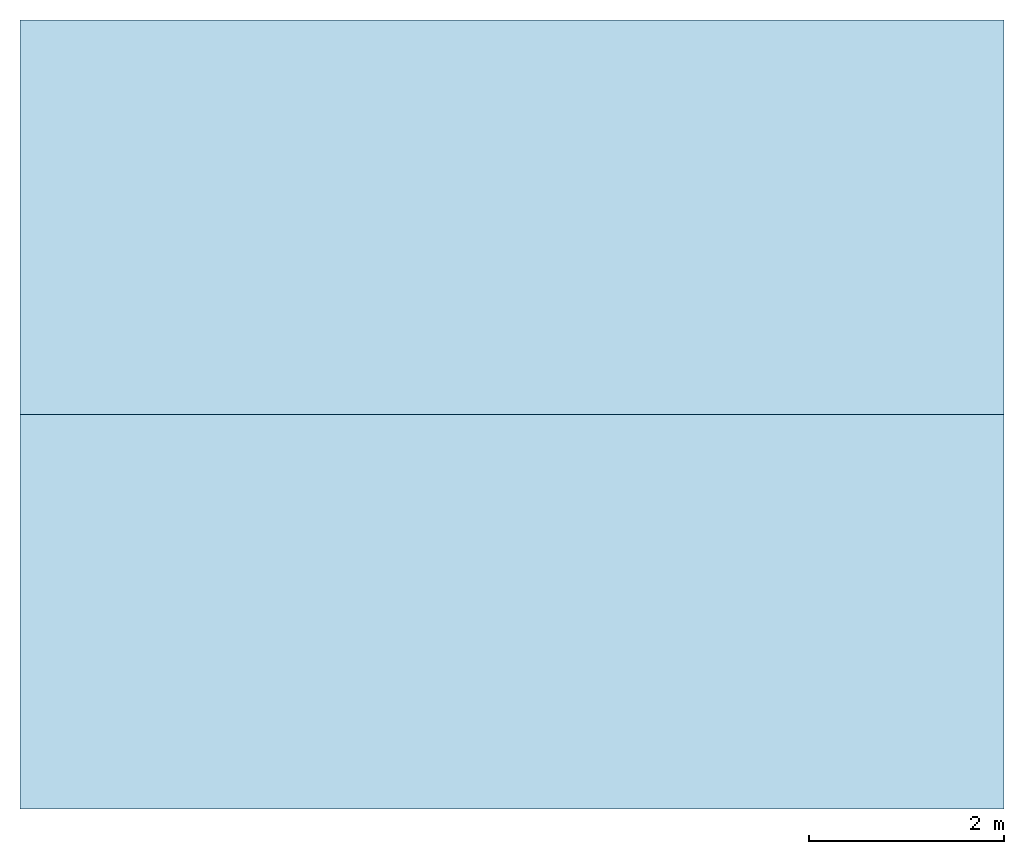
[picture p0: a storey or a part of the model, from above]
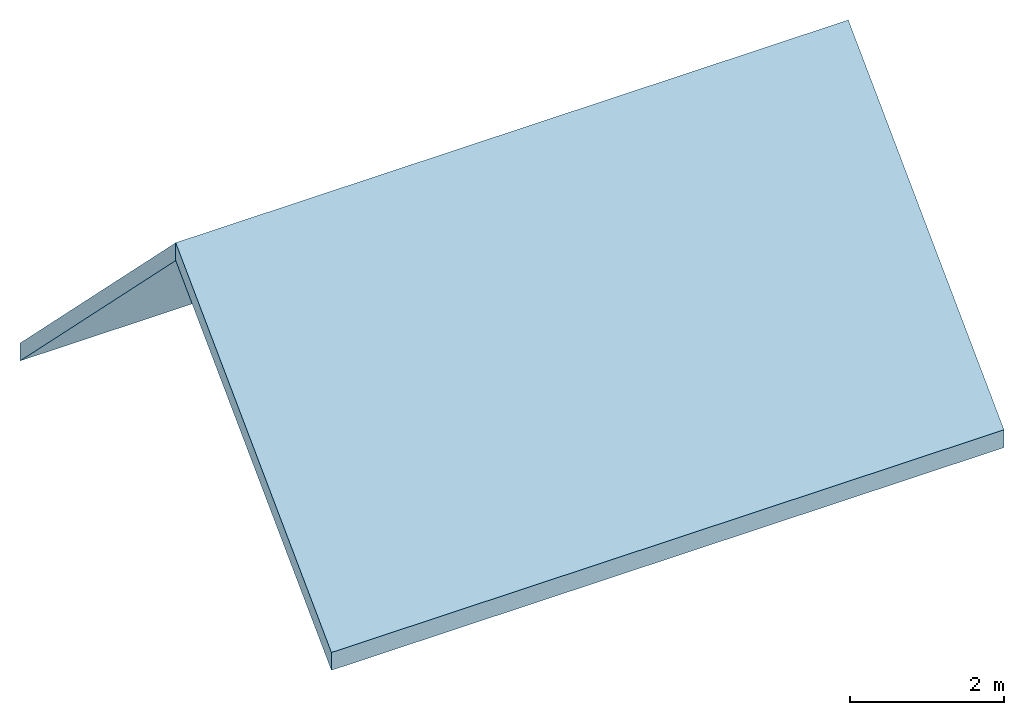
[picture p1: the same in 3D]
Properties of the parts of a building model (IFC2X3)

# File
Description: ViewDefinition [CoordinationView]
Time: 2014-10-18T11:21:26
Written by: The EXPRESS Data Manager Version 5.01.0100.02.64mod : 6 Jun 2012
Made in: 20130308_1515(x64) - Exporter 2014.0.2013.0308 - Default UI
Comment: STEP Physical File produced by: The EXPRESS Data Manager Version 5.01.0100.02.64mod : 6 Jun 2012 * Module: EDMstepFileFactory/EDMstandAlone * Creation date: Sat Oct 18 11:21:26 2014 * Host: PC-david * Database: C:\Users\DEVEAUX\AppData\Local\Temp\{E35612F2-2FBD-463F-806F-01D8CE0484EC}\ifc * Database version: 5507 * Database creation date: Sat Oct 18 11:21:22 2014 * Schema: IFC2X3 * Model: DataRepository.ifc * Model creation date: Sat Oct 18 11:21:22 2014 * Header model: DataRepository.ifc_HeaderModel * Header model creation date: Sat Oct 18 11:21:22 2014 * EDMuser: sdai-user * EDMgroup: sdai-group * License ID and type: 5605 : Permanent license. Expiry date: * EDMstepFileFactory options: 020000

# IfcProject
LongName: C:\Users\DEVEAUX\Documents\maison_01.ifc

# IfcSite, Default
RefLatitude: 48, 52, 53, 759999; RefLongitude: 2, 25, 58, 79999; RefElevation: 0 m

# IfcBuilding
Pset_BuildingCommon - NumberOfStoreys: 2

# IfcBuildingStorey (2)
Données d'identification - Structure: no; Etage de bâtiment: yes
Cotes - Hauteur de calcul: 0 m
Graphismes - Motif des lignes: Tiret point; Valeur par défaut du symbole à l'extrémité 2: yes; Epaisseur des lignes: 1; Valeur par défaut du symbole à l'extrémité 1: no; Couleur: 12632256; Symbole: FR_Marqueur de niveau - Point triangulaire: FR_Marqueur de niveau - Point triangulaire
Contraintes - Base de l'élévation: Point de base du projet
Name | LongName = Nom | Elevation (m) | Elévation (m)
Niveau 00 | Niveau 00 | 6.8783e-12 | 0
Niveau 01 | Niveau 01 | 3 | 3

# IfcSpace (9)
In: Niveau 00
InteriorOrExteriorSpace: INTERNAL
Contraintes - Limite supérieure: Niveau: Niveau 00; Niveau: Niveau: Niveau 00; Décalage limite: 2.4384 m; Décalage inférieur: 0 m
Phase de construction - Phase: Nouvelle construction
Cotes - Hauteur non liée: 2.4384 m; Hauteur de calcul: 0 m
Name | LongName = Nom | GSA BIM Area (m2) = Surface (m2) | Numéro | Périmètre (m) | Reference
10 | Séjour | 17.9204 | 10 | 17.15 | Séjour 10
11 | Cuisine | 7.00693 | 11 | 11.17 | Cuisine 11
12 | Entrée | 7.27615 | 12 | 14.07 | Entrée 12
13 | WC | 2.42 | 13 | 6.6 | WC 13
14 | S de B | 5.83 | 14 | 9.7 | S de B 14
15 | Rgt 1 | 0.945 | 15 | 4.35 | Rgt 1 15
16 | Rgt 2 | 0.945 | 16 | 4.35 | Rgt 2 16
17 | Chambre 1 | 8.3525 | 17 | 11.64 | Chambre 1 17
18 | Chambre 2 | 8.125 | 18 | 11.5 | Chambre 2 18

# IfcBuildingElementProxy: Texte 3D:Texte 3D 1
In: Niveau 00
Graphismes - Texte: Maison N°1; Alignement horizontal: Gauche
Phase de construction - Phase de création: Nouvelle construction
Cotes - Profondeur: 0.15 m
Données d'identification - Sous-catégorie: -2000151
Contraintes - Plan de construction: Niveau : Niveau 00
Pset_BuildingElementProxyCommon - Reference: Texte 3D 1
Texte - Italique: no; Taille du texte: 0.6 m; Police de texte: Arial; Gras: no

# IfcCovering: Plafond composé:Plafond avec isolation 2, Plafond composé:Plafond avec isolation 2:113292
In: Niveau 00
PredefinedType: CEILING; Material: Isolant 0.1 m, Faux-Plafond par Défaut 0.013 m
Cotes - Surface: 60.7796 m2; Volume: 6.86809 m3; Périmètre: 31.44 m
Contraintes - Limite de pièce: yes; Décalage par rapport au niveau: 2.6 m; Niveau: Niveau: Niveau 00
Phase de construction - Phase de création: Nouvelle construction
Pset_CoveringCommon - Reference: Plafond avec isolation 2; TotalThickness: 0.113 m
Propriétés analytiques - Coefficient d'absorbance: 0.1; Rugosité: 1
Construction - Epaisseur: 0.113 m
Graphismes - Couleur vue détail faible: 0

# IfcCovering: Plafond de base:Faux plafond 300 x 300 mm (2)
In: Niveau 00
PredefinedType: CEILING
Cotes - Périmètre: 31.44 m; Surface: 60.7796 m2
Phase de construction - Phase de création: Nouvelle construction
Contraintes - Limite de pièce: yes; Niveau: Niveau: Niveau 00; Décalage par rapport au niveau: 2.6 m
Pset_CoveringCommon - Reference: Faux plafond 300 x 300 mm
Propriétés analytiques - Rugosité: 1; Coefficient d'absorbance: 0.1
Matériaux et finitions - Matériau: Faux-Plafond par Défaut
Name (Plafond de base:Faux plafond 300 x 300 mm:...)
113275
113283

# IfcDoor: 143 x 204 - (140), FR_Double Vitrée Modèle 1:143 x 204 - (140):99876
In: Niveau 00
Type - OperationType: DOUBLE_DOOR_SINGLE_SWING; ParameterTakesPrecedence: no; Sizeable: no; Material: Poignée Porte, Dormants Portes, Verre, Panneaux Portes
OverallHeight: 2.075 m; OverallWidth: 1.5 m
Autre - Hauteur du linteau: 2.04 m
Contraintes - Hauteur de l'appui: 0 m; Niveau: Niveau: Niveau 00; Déc. Vitre (Auto): 0.017 m; Sys: 0 m
Phase de construction - Phase de création: Nouvelle construction
Données d'identification - Identifiant: 34; Marque de type: 19
Pset_DoorCommon - Reference: 143 x 204 - (140); IsExternal: no
Matériaux et finitions - Dormants: Dormants Portes; Panneau: Panneaux Portes; Poignée: Poignée Porte
Propriétés analytiques - Construction analytique: <Aucun>
Cotes - Larg. Dormants: 0.035 m; Largeur: 1.43 m; Elev. Poignée: 0.9 m; Retour: 0.01 m; Hauteur: 2.04 m; Epaisseur: 0.04 m
Construction - Fonction: Intérieur; Fermeture du mur: Aucun

# IfcDoor: 163 x 204 - (160), FR_Double Vitrée Modèle 1:163 x 204 - (160):101490
In: Niveau 00
Type - OperationType: DOUBLE_DOOR_SINGLE_SWING; ParameterTakesPrecedence: no; Sizeable: no; Material: Poignée Porte, Dormants Portes, Verre, Panneaux Portes
OverallHeight: 2.075 m; OverallWidth: 1.7 m
Contraintes - Niveau: Niveau: Niveau 00; Hauteur de l'appui: 0 m; Déc. Vitre (Auto): 0.017 m; Sys: 0 m
Données d'identification - Identifiant: 43; Marque de type: 20
Phase de construction - Phase de création: Nouvelle construction
Autre - Hauteur du linteau: 2.04 m
Pset_DoorCommon - Reference: 163 x 204 - (160); IsExternal: yes
Construction - Fonction: Intérieur; Fermeture du mur: Par hôte
Cotes - Epaisseur: 0.04 m; Larg. Dormants: 0.035 m; Largeur: 1.63 m; Hauteur: 2.04 m; Elev. Poignée: 0.9 m; Retour: 0.01 m
Matériaux et finitions - Poignée: Poignée Porte; Panneau: Panneaux Portes; Dormants: Dormants Portes
Propriétés analytiques - Construction analytique: <Aucun>

# IfcDoor: 183 x 204 - (180), FR_Double Vitrée Modèle 1:183 x 204 - (180):101860
In: Niveau 00
Type - OperationType: DOUBLE_DOOR_SINGLE_SWING; ParameterTakesPrecedence: no; Sizeable: no; Material: Poignée Porte, Dormants Portes, Verre, Panneaux Portes
OverallHeight: 2.075 m; OverallWidth: 1.9 m
Phase de construction - Phase de création: Nouvelle construction
Autre - Hauteur du linteau: 2.04 m
Données d'identification - Identifiant: 44; Marque de type: 21
Contraintes - Hauteur de l'appui: 0 m; Niveau: Niveau: Niveau 00; Déc. Vitre (Auto): 0.017 m; Sys: 0 m
Pset_DoorCommon - Reference: 183 x 204 - (180); IsExternal: yes
Propriétés analytiques - Construction analytique: <Aucun>
Matériaux et finitions - Dormants: Dormants Portes; Panneau: Panneaux Portes; Poignée: Poignée Porte
Construction - Fermeture du mur: Par hôte; Fonction: Intérieur
Cotes - Retour: 0.01 m; Elev. Poignée: 0.9 m; Hauteur: 2.04 m; Larg. Dormants: 0.035 m; Epaisseur: 0.04 m; Largeur: 1.83 m

# IfcDoor: 83 x 204 - (80) (2)
In: Niveau 00
Type - OperationType: SINGLE_SWING_LEFT; ParameterTakesPrecedence: no; Sizeable: no; Material: Poignée Porte, Dormants Portes, Panneaux Portes
OverallHeight: 2.075 m; OverallWidth: 0.9 m
Phase de construction - Phase de création: Nouvelle construction
Contraintes - Hauteur de l'appui: 0 m; Niveau: Niveau: Niveau 00
Autre - Hauteur du linteau: 2.04 m
Pset_DoorCommon - Reference: 83 x 204 - (80); IsExternal: no
Données d'identification - Marque de type: 9
Matériaux et finitions - Dormants: Dormants Portes; Poignée: Poignée Porte; Panneau: Panneaux Portes
Construction - Fermeture du mur: Par hôte; Fonction: Intérieur
Cotes - Hauteur: 2.04 m; Larg. Dormants: 0.035 m; Epaisseur: 0.04 m; Retour: 0.01 m; Largeur: 0.83 m; Elev. Poignée: 0.9 m
Propriétés analytiques - Construction analytique: <Aucun>
Name (FR_Simple (R):83 x 204 - (80):...) | Identifiant
100468 | 36
100601 | 37

# IfcDoor: 83 x 204 - (80) (2)
In: Niveau 00
Type - OperationType: SINGLE_SWING_RIGHT; ParameterTakesPrecedence: no; Sizeable: no; Material: Poignée Porte, Dormants Portes, Panneaux Portes
OverallHeight: 2.075 m; OverallWidth: 0.9 m
Contraintes - Niveau: Niveau: Niveau 00; Hauteur de l'appui: 0 m
Phase de construction - Phase de création: Nouvelle construction
Autre - Hauteur du linteau: 2.04 m
Pset_DoorCommon - Reference: 83 x 204 - (80); IsExternal: no
Données d'identification - Marque de type: 9
Matériaux et finitions - Dormants: Dormants Portes; Poignée: Poignée Porte; Panneau: Panneaux Portes
Construction - Fermeture du mur: Par hôte; Fonction: Intérieur
Cotes - Hauteur: 2.04 m; Larg. Dormants: 0.035 m; Epaisseur: 0.04 m; Retour: 0.01 m; Largeur: 0.83 m; Elev. Poignée: 0.9 m
Propriétés analytiques - Construction analytique: <Aucun>
Name (FR_Simple (R):83 x 204 - (80):...) | Identifiant
100434 | 35
100674 | 38

# IfcDoor: 93 x 210 - (90), FR_Entrée Modèle 1:93 x 210 - (90):99688
In: Niveau 00
Type - OperationType: SINGLE_SWING_RIGHT; ParameterTakesPrecedence: no; Sizeable: no; Material: Poignée Porte Entrée, Dormants Porte Entrée, Verre, Panneaux Porte Entrée
OverallHeight: 2.16 m; OverallWidth: 1.05 m
Contraintes - Hauteur de l'appui: 0 m; Niveau: Niveau: Niveau 00; Tiers Hauteur (Auto): 0.7 m; Haut. Deco (Auto): 0.315 m; Déc. Vitre (Auto): 0.02 m; Sys: 0 m
Données d'identification - Identifiant: 33; Marque de type: 4
Phase de construction - Phase de création: Nouvelle construction
Autre - Hauteur du linteau: 2.1 m
Pset_DoorCommon - Reference: 93 x 210 - (90); IsExternal: yes
Cotes - Larg. Feuillure: 0.05 m; Prof. Feuillure: 0.07 m; Hauteur: 2.1 m; Elev. Poignée: 0.9 m; Largeur: 0.93 m; Epaisseur: 0.05 m
Construction - Fermeture du mur: Par hôte; Fonction: Intérieur
Propriétés analytiques - Construction analytique: <Aucun>
Matériaux et finitions - Poignée: Poignée Porte Entrée; Dormants: Dormants Porte Entrée; Panneau: Panneaux Porte Entrée

# IfcDoor: FR_Placard Pliante (2)
In: Niveau 00
Type - ParameterTakesPrecedence: no; Sizeable: no; Material: Encadrement Placards, Portes Placards
OverallHeight: 2.1 m; OverallWidth: 0.9 m
Contraintes - Hauteur de l'appui: 0 m; Niveau: Niveau: Niveau 00; Sys: 0 m; Demi Larg. (Auto): 0.45 m
Phase de construction - Phase de création: Nouvelle construction
Autre - Hauteur du linteau: 2.1 m
Pset_DoorCommon - Reference: FR_Placard Pliante; IsExternal: no
Matériaux et finitions - Panneau: Portes Placards; Encadrement: Encadrement Placards; Poignée: Encadrement Placards
Données d'identification - Marque de type: 6
Construction - Fermeture du mur: Aucun; Fonction: Intérieur
Propriétés analytiques - Construction analytique: <Aucun>
Cotes - Hauteur: 2.1 m; Largeur de l'encadrement: 0.05 m; Largeur: 0.9 m; Elev. Poignée: 0.91 m
Name (FR_Placard Pliante:FR_Placard Pliante:...) | Identifiant
100836 | 39
100930 | 40

# IfcOpeningElement: Opening (15)
In: Niveau 00
Name
4 x  | Contraintes - Hauteur non contrainte: 2.4384 m; Contrainte inférieure: Niveau: Niveau 00; Partie supérieure attachée: yes; Ligne de justification: Nu porteur: Extérieur; Décalage supérieur: 0 m; Décalage inférieur: 0 m; Partie inférieure attachée: no; Extension supérieure: 0 m; Limite de pièce: yes; Lié au volume: no; Extension inférieure: 0 m; Structure - Activer le modèle analytique: no; Structure: no; Utilisation structurelle: Non porteur; Phase de construction - Phase de création: Nouvelle construction; Cotes - Longueur: 9.18 m; Volume: 7.77406 m3; Surface: 25.322 m2; Construction - Largeur: 0.32 m; Retournement aux ouvertures: Les deux; Fonction: Extérieur; Retournement aux extrémités: Aucun(e); Matériaux et finitions - Matériau structurel: Voile BA; Données d'identification - Commentaires du type: Exterieur Voile BA 20 + Isolant 10; Graphismes - Couleur vue détail faible: 0; Propriétés analytiques - Rugosité: 1; Coefficient d'absorbance: 0.1
 | Contraintes - Hauteur non contrainte: 2.4384 m; Contrainte inférieure: Niveau: Niveau 00; Partie supérieure attachée: yes; Ligne de justification: Nu porteur: Extérieur; Décalage supérieur: 0 m; Décalage inférieur: 0 m; Partie inférieure attachée: no; Extension supérieure: 0 m; Limite de pièce: yes; Lié au volume: no; Extension inférieure: 0 m; Structure - Activer le modèle analytique: no; Structure: no; Utilisation structurelle: Non porteur; Phase de construction - Phase de création: Nouvelle construction; Cotes - Longueur: 7.18 m; Volume: 10.8745 m3; Surface: 33.9586 m2; Construction - Largeur: 0.32 m; Retournement aux ouvertures: Les deux; Fonction: Extérieur; Retournement aux extrémités: Aucun(e); Matériaux et finitions - Matériau structurel: Voile BA; Données d'identification - Commentaires du type: Exterieur Voile BA 20 + Isolant 10; Graphismes - Couleur vue détail faible: 0; Propriétés analytiques - Rugosité: 1; Coefficient d'absorbance: 0.1
 | Contraintes - Hauteur non contrainte: 2.4384 m; Contrainte inférieure: Niveau: Niveau 00; Partie supérieure attachée: yes; Ligne de justification: Nu porteur: Extérieur; Décalage supérieur: 0 m; Décalage inférieur: 0 m; Partie inférieure attachée: no; Extension supérieure: 0 m; Limite de pièce: yes; Lié au volume: no; Extension inférieure: 0 m; Structure - Activer le modèle analytique: no; Structure: no; Utilisation structurelle: Non porteur; Phase de construction - Phase de création: Nouvelle construction; Cotes - Longueur: 9.18 m; Volume: 7.43287 m3; Surface: 24.5702 m2; Construction - Largeur: 0.32 m; Retournement aux ouvertures: Les deux; Fonction: Extérieur; Retournement aux extrémités: Aucun(e); Matériaux et finitions - Matériau structurel: Voile BA; Données d'identification - Commentaires du type: Exterieur Voile BA 20 + Isolant 10; Graphismes - Couleur vue détail faible: 0; Propriétés analytiques - Rugosité: 1; Coefficient d'absorbance: 0.1
FR_Double Vitrée Modèle 1:143 x 204 - (140):99876:1
FR_Simple (R):83 x 204 - (80):100434:1
FR_Simple (R):83 x 204 - (80):100468:1
FR_Simple (R):83 x 204 - (80):100601:1
FR_Simple (R):83 x 204 - (80):100674:1
FR_Placard Pliante:FR_Placard Pliante:100836:1
FR_Placard Pliante:FR_Placard Pliante:100930:1
FR_Double Vitrée Modèle 1:163 x 204 - (160):101490:1
FR_Double Vitrée Modèle 1:183 x 204 - (180):101860:1

# IfcRoof: Toit de base:Toit - 200 mm, Toit de base:Toit - 200 mm:104972
In: Niveau 01
Construction - Coupe en chevron: Coupe verticale; Profondeur du bord de toiture: 0 m; Hauteur maximale de l'arrête: 7.03284 m; Chevron ou ferme: Ferme; Epaisseur par défaut: 0.2 m
Cotes - Volume: 23.1394 m3; Epaisseur: 0.2 m; Surface: 115.697 m2; Inclinaison: 1
Contraintes - Niveau de base: Niveau: Niveau 01; Décalage inférieur à partir du niveau: 0 m; Lié au volume: no; Limite de pièce: yes; Décalage de la coupure: 0 m
Phase de construction - Phase de création: Nouvelle construction
Pset_RoofCommon - Reference: Toit - 200 mm; IsExternal: yes; TotalArea: 115.697 m2; ProjectedArea: 81.81 m2
Propriétés analytiques - Coefficient d'absorbance: 0.1; Rugosité: 1
Graphismes - Couleur vue détail faible: 0

# IfcSlab: Toit de base:Toit - 200 mm (2)
In: Niveau 01
PredefinedType: ROOF; Material: Toit par défaut 0.2 m
Construction - Coupe en chevron: Coupe verticale; Profondeur du bord de toiture: 0 m; Hauteur maximale de l'arrête: 7.03284 m; Chevron ou ferme: Ferme; Epaisseur par défaut: 0.2 m
Cotes - Volume: 23.1394 m3; Epaisseur: 0.2 m; Surface: 115.697 m2; Inclinaison: 1
Contraintes - Niveau de base: Niveau: Niveau 01; Décalage inférieur à partir du niveau: 0 m; Lié au volume: no; Limite de pièce: yes; Décalage de la coupure: 0 m
Phase de construction - Phase de création: Nouvelle construction
Pset_SlabCommon - Reference: Toit - 200 mm; IsExternal: yes; LoadBearing: yes
Propriétés analytiques - Coefficient d'absorbance: 0.1; Rugosité: 1
Graphismes - Couleur vue détail faible: 0

# IfcWallStandardCase: Mur de base:Ext. Voile BA 20 + Isolant 10 (4)
In: Niveau 00
Type - PredefinedType: STANDARD; Material: Enduit 0.02 m, Voile BA 0.2 m, Isolant 0.1 m
Type - Construction - Largeur: 0.32 m; Retournement aux ouvertures: Les deux; Fonction: Extérieur; Retournement aux extrémités: Aucun(e)
Type - Matériaux et finitions - Matériau structurel: Voile BA
Type - Données d'identification - Commentaires du type: Exterieur Voile BA 20 + Isolant 10
Type - Graphismes - Couleur vue détail faible: 0
Type - Propriétés analytiques - Rugosité: 1; Coefficient d'absorbance: 0.1
Contraintes - Hauteur non contrainte: 2.4384 m; Contrainte inférieure: Niveau: Niveau 00; Partie supérieure attachée: yes; Ligne de justification: Nu porteur: Extérieur; Décalage supérieur: 0 m; Décalage inférieur: 0 m; Partie inférieure attachée: no; Extension supérieure: 0 m; Limite de pièce: yes; Lié au volume: no; Extension inférieure: 0 m
Structure - Activer le modèle analytique: no; Structure: no; Utilisation structurelle: Non porteur
Phase de construction - Phase de création: Nouvelle construction
Pset_WallCommon - Reference: Ext. Voile BA 20 + Isolant 10; LoadBearing: no; ExtendToStructure: yes; IsExternal: yes
Name (Mur de base:Ext. Voile BA 20 + Isolant 10:...) | Longueur (m) | Volume (m3) | Surface (m2)
98439 | 9.18 | 7.77406 | 25.322
98514 | 7.18 | 10.8745 | 33.9586
98574 | 9.18 | 7.43287 | 24.5702
98632 | 7.18 | 9.79123 | 30.5976

# IfcWallStandardCase: Mur de base:Int. Platre 70 mm (9)
In: Niveau 00
Type - PredefinedType: STANDARD; Material: Mur par défaut 0.07 m
Type - Données d'identification - Commentaires du type: Int. Platre 70 mm
Type - Construction - Retournement aux ouvertures: Ne pas retourner; Fonction: Intérieur; Retournement aux extrémités: Aucun(e); Largeur: 0.07 m
Type - Propriétés analytiques - Rugosité: 1; Coefficient d'absorbance: 0.1
Type - Graphismes - Couleur vue détail faible: 0
Structure - Structure: no; Activer le modèle analytique: no; Utilisation structurelle: Non porteur
Contraintes - Décalage inférieur: 0 m; Ligne de justification: Nu porteur: Extérieur; Partie inférieure attachée: no; Extension inférieure: 0 m; Partie supérieure attachée: no; Contrainte inférieure: Niveau: Niveau 00; Limite de pièce: yes; Décalage supérieur: 0 m; Lié au volume: no; Extension supérieure: 0 m
Phase de construction - Phase de création: Nouvelle construction
Pset_WallCommon - Reference: Int. Platre 70 mm; LoadBearing: no; ExtendToStructure: no; IsExternal: no
Name (Mur de base:Int. Platre 70 mm:...) | Hauteur non contrainte (m) | Longueur (m) | Volume (m3) | Surface (m2)
98878 | 2.4384 | 7.18 | 0.953045 | 13.6149
98999 | 2.4384 | 2.395 | 0.387462 | 5.53517
99075 | 2.4384 | 4.015 | 0.258278 | 3.68969
99176 | 2.4384 | 2.395 | 0.375514 | 5.36448
99301 | 2.4384 | 5.335 | 0.483586 | 6.90838
99458 | 2.4384 | 3.445 | 0.554736 | 7.9248
99600 | 1.15499 | 1.755 | 0.128954 | 1.84221
100125 | 2.4384 | 1.34 | 0.216774 | 3.09677
100261 | 2.4384 | 1.77 | 0.268834 | 3.84048

# IfcWindow: 120x125, FR_2 Vantaux Appui Alu + Croisillons:120x125:101141
In: Niveau 00
Type - ParameterTakesPrecedence: no; Sizeable: no; Material: Huisserie, Appui, Verre
OverallHeight: 1.39942 m; OverallWidth: 2.46 m
Phase de construction - Phase de création: Nouvelle construction
Données d'identification - Identifiant: 21; Marque de type: 12
Autre - Hauteur du linteau: 2.15 m
Contraintes - Niveau: Niveau: Niveau 00; Hauteur de l'appui: 0.9 m
Pset_WindowCommon - Reference: 120x125; IsExternal: yes
Propriétés analytiques - Construction analytique: <Aucun>
Cotes - Feuillure Larg.: 0.06 m; Largeur: 1.2 m; Hauteur: 1.25 m; Profondeur Huisserie: 0.04 m; Allege Defaut: 0.9 m; Dormant Larg.: 0.06 m; Ouvrant Larg.: 0.07 m
Construction - Fermeture du mur: Par hôte
Graphismes - Type de petits bois: Petits Bois 2x2x4: Petits Bois 2x2x4
Matériaux et finitions - Huisserie: Huisserie

# IfcWindow: 140 x 135, FR_Coulissant Appui Alu:140 x 135:101963
In: Niveau 00
Type - ParameterTakesPrecedence: no; Sizeable: no; Material: Appui, Huisserie, Verre
OverallHeight: 1.65997 m; OverallWidth: 1.5 m
Données d'identification - Identifiant: 24; Marque de type: 7
Autre - Hauteur du linteau: 2.25 m
Phase de construction - Phase de création: Nouvelle construction
Contraintes - Niveau: Niveau: Niveau 00; Hauteur de l'appui: 0.9 m
Pset_WindowCommon - Reference: 140 x 135; IsExternal: yes
Cotes - Hauteur: 1.35 m; Largeur: 1.4 m; Dormant Larg.: 0.04 m; Ouvrant Larg.: 0.06 m; Allege Defaut: 0.9 m; Profondeur Huisserie: 0.08 m
Construction - Fermeture du mur: Par hôte
Propriétés analytiques - Construction analytique: <Aucun>
Matériaux et finitions - Huisserie: Huisserie

# IfcWindow: 160 x 135, FR_3 Vantaux Appui Alu:160 x 135:101635
In: Niveau 00
Type - ParameterTakesPrecedence: no; Sizeable: no; Material: Appui, Huisserie, Verre
OverallHeight: 1.49942 m; OverallWidth: 1.70004 m
Autre - Hauteur du linteau: 1.95 m
Phase de construction - Phase de création: Nouvelle construction
Données d'identification - Identifiant: 23; Marque de type: 6
Contraintes - Niveau: Niveau: Niveau 00; Hauteur de l'appui: 0.6 m; Axe Vertical: 0.075 m
Pset_WindowCommon - Reference: 160 x 135; IsExternal: yes
Cotes - Vantail Centre Larg.: 0.04 m; Allege Defaut: 0.6 m; Profondeur Huisserie: 0.04 m; Vantail Larg.: 0.04 m; Vantail Central Larg: 0.65 m; Hauteur: 1.35 m; Largeur: 1.6 m; Dormant Larg.: 0.04 m
Propriétés analytiques - Construction analytique: <Aucun>
Construction - Fermeture du mur: Par hôte
Matériaux et finitions - Huisserie: Huisserie

# IfcWindow: 60x105, FR_1 Vantail Appui Alu + Croisillons:60x105:100980
In: Niveau 00
Type - ParameterTakesPrecedence: no; Sizeable: no; Material: Huisserie, Appui, Verre
OverallHeight: 1.35997 m; OverallWidth: 0.7 m
Autre - Hauteur du linteau: 1.95 m
Données d'identification - Identifiant: 19; Marque de type: 10
Phase de construction - Phase de création: Nouvelle construction
Contraintes - Niveau: Niveau: Niveau 00; Hauteur de l'appui: 0.9 m
Pset_WindowCommon - Reference: 60x105; IsExternal: yes
Graphismes - Petits bois: yes
Propriétés analytiques - Construction analytique: <Aucun>
Matériaux et finitions - Huisserie: Huisserie
Cotes - Dormant Larg.: 0.07 m; Ouvrant Larg.: 0.06 m; Profondeur Huisserie: 0.06 m; Largeur: 0.6 m; Allege Defaut: 0.9 m; Hauteur: 1.05 m
Construction - Fermeture du mur: Par hôte

# IfcWindow: 80x115, FR_1 Vantail Appui Alu + Croisillons:80x115:101045
In: Niveau 00
Type - ParameterTakesPrecedence: no; Sizeable: no; Material: Huisserie, Appui, Verre
OverallHeight: 1.45997 m; OverallWidth: 0.9 m
Contraintes - Hauteur de l'appui: 0.9 m; Niveau: Niveau: Niveau 00
Phase de construction - Phase de création: Nouvelle construction
Données d'identification - Identifiant: 20; Marque de type: 11
Autre - Hauteur du linteau: 2.05 m
Pset_WindowCommon - Reference: 80x115; IsExternal: yes
Cotes - Largeur: 0.8 m; Allege Defaut: 0.9 m; Dormant Larg.: 0.07 m; Profondeur Huisserie: 0.06 m; Ouvrant Larg.: 0.06 m; Hauteur: 1.15 m
Graphismes - Petits bois: yes
Construction - Fermeture du mur: Par hôte
Propriétés analytiques - Construction analytique: <Aucun>
Matériaux et finitions - Huisserie: Huisserie
